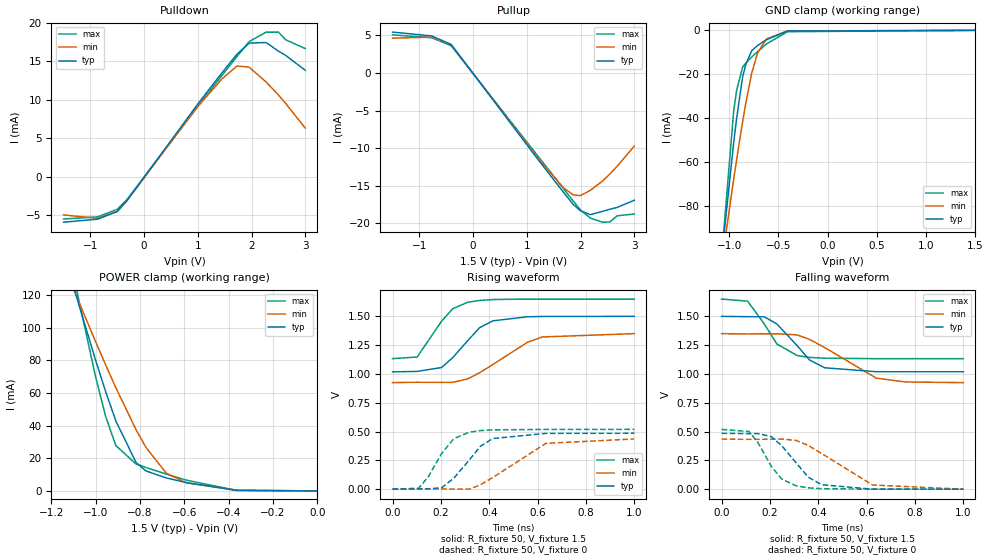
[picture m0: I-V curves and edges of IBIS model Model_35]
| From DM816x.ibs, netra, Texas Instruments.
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| Model based on original model for BSHTLTCSCDVGPBFZ
|   Sub model FAST_4MA_10PER_1P5
[model]   Model_35
|[Description]  1.5V-3-STATE-X-FAST, 4MA, +-10%
|[Input Load]
|[Output Drive] FAST, 4MA
|Voltage   1.5V
|Mode   3-STATE
Model_type   3-state
Polarity   Non-Inverting
Enable   Active-Low
Cref =  15.0000pF
Rref =  100.0000M
Vref =  0V
Vmeas =  0.75
C_comp   1.5249p   1.4275p   1.6205p
[Model Spec]
[Temperature Range]   25   125   -40
[Voltage Range]   1.5   1.35   1.65
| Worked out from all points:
|   slope of the pulldown table from 0 to 0.225 V, typ, clamps not added: 103 ohm
|   slope of the pullup table from 0 to 0.225 V, typ, clamps not added: 103 ohm
|   GND clamp passes 1 mA (typ) near -0.47 V on its own axis
|   POWER clamp passes 1 mA (typ) near -0.42 V on its own axis
|   rising waveform, R_fixture 50, V_fixture 1.5: 20-80 % time 125ps typ, 190ps min, 98.5ps max; typ from 1.02 V to 1.5 V
|   rising waveform, R_fixture 50, V_fixture 0: 20-80 % time 118ps typ, 179ps min, 93.9ps max; typ from 0 V to 0.485 V
|   falling waveform, R_fixture 50, V_fixture 1.5: 20-80 % time 123ps typ, 193ps min, 96.8ps max; typ from 1.5 V to 1.02 V
|   falling waveform, R_fixture 50, V_fixture 0: 20-80 % time 118ps typ, 186ps min, 92.7ps max; typ from 0.485 V to 0 V
[POWER_clamp]
-1.5V     321.6mA    260.6mA    415.8mA
-1.091V   121.1mA    120.8mA    126.6mA
-1.076V   114.1mA    115.8mA    116.8mA
-1V       79.88mA    91.3mA     69.56mA
-954.5mV  60.58mA    77.05mA    45.34mA
-909.1mV  42.84mA    63.2mA     27.8mA
-818.2mV  17.47mA    37.6mA     16.51mA
-772.7mV  12.19mA    26.53mA    14.33mA
-681.8mV  7.985mA    10.89mA    10.33mA
-590.9mV  5.092mA    4.952mA    6.596mA
-363.6mV  298.9uA    465.6uA    298.1uA
0V        1.518nA    23.05nA    396.5pA
[Pulldown]
-1.5V     -5.88mA    -4.94mA    -5.47mA
-863.6mV  -5.487mA   -5.379mA   -5.186mA
-500mV    -4.486mA   -4.503mA   -4.211mA
-318.2mV  -3.077mA   -3.07mA    -2.94mA
1V        9.473mA    9.16mA     9.156mA
1.455V    13.57mA    12.77mA    13.23mA
1.727V    15.92mA    14.4mA     15.62mA
1.955V    17.38mA    14.26mA    17.57mA
2.273V    17.45mA    12.32mA    18.81mA
2.5V      16.34mA    10.65mA    18.81mA
2.636V    15.78mA    9.54mA     17.81mA
3V        13.85mA    6.33mA     16.67mA
[Pullup]
-1.5V     5.43mA     4.62mA     5.06mA
-772.7mV  4.923mA    4.757mA    4.681mA
-409.1mV  3.79mA     3.753mA    3.62mA
1.227V    -11.69mA   -11.51mA   -11.25mA
1.682V    -15.87mA   -15.27mA   -15.39mA
1.864V    -17.48mA   -16.22mA   -17.03mA
2V        -18.33mA   -16.3mA    -18.23mA
2.182V    -18.84mA   -15.6mA    -19.29mA
2.409V    -18.4mA    -14.37mA   -19.84mA
2.545V    -18.12mA   -13.43mA   -19.81mA
2.682V    -17.87mA   -12.4mA    -18.99mA
3V        -16.92mA   -9.72mA    -18.75mA
[GND_clamp]
-1.5V     -310mA     -250.5mA   -402.4mA
-1.076V   -103.5mA   -106.1mA   -105.2mA
-1.045V   -89.74mA   -96.32mA   -85.93mA
-954.5mV  -51.19mA   -67.85mA   -36.85mA
-924.2mV  -40.06mA   -58.84mA   -27.27mA
-863.6mV  -21.23mA   -41.55mA   -16.73mA
-833.3mV  -15.79mA   -33.74mA   -15.03mA
-772.7mV  -9.342mA   -19.74mA   -12.19mA
-712.1mV  -6.927mA   -10.35mA   -9.702mA
-621.2mV  -4.26mA    -3.894mA   -6.224mA
-409.1mV  -336.9uA   -288.9uA   -618.6uA
1.5V      1.518nA    2.298uA    269.6pA
[Ramp]
dV/dt_f   0.38584/0.19087369n   0.340824/0.2796553n   0.41424/0.15390254n
dV/dt_r 0.38881204/0.18228362n 0.35035216/0.25786987n 0.41518698/0.14899493n
R_load = 50
[Rising Waveform]
R_fixture = 50
V_fixture = 1.5
V_fixture_min = 1.35
V_fixture_max = 1.65
0s        1.018V     925mV      1.133V
101.8ps   1.022V     927.9mV    1.147V
202.9ps   1.056V     926.8mV    1.458V
249.3ps   1.142V     927.2mV    1.567V
310.6ps   1.288V     956.7mV    1.622V
359.9ps   1.401V     1.01V      1.638V
415ps     1.461V     1.082V     1.646V
557.2ps   1.496V     1.274V     1.65V
619.4ps   1.499V     1.321V     1.65V
1ns       1.5V       1.35V      1.65V
[Rising Waveform]
R_fixture = 50
V_fixture = 0
V_fixture_min = 0
V_fixture_max = 0
0s        0V         0V         0V
108ps     3.692mV    3.336mV    8.042mV
148.5ps   2.516mV    2.612mV    109.7mV
203.4ps   12.94mV    2.18mV     310.8mV
253.5ps   95.47mV    0V         438.2mV
316.7ps   250.8mV    0V         494.3mV
362.5ps   370.4mV    36.85mV    508.2mV
414.5ps   439.3mV    100.9mV    514.7mV
634.5ps   484.3mV    397.9mV    518.8mV
1ns       485.4mV    435.6mV    518.9mV
[Falling Waveform]
R_fixture = 50
V_fixture = 1.5
V_fixture_min = 1.35
V_fixture_max = 1.65
0s        1.499V     1.349V     1.649V
107.7ps   1.496V     1.346V     1.631V
176.4ps   1.495V     1.348V     1.434V
228.8ps   1.433V     1.348V     1.259V
313ps     1.244V     1.338V     1.159V
363.6ps   1.121V     1.299V     1.143V
426.1ps   1.053V     1.229V     1.136V
640ps     1.019V     963mV      1.132V
760ps     1.018V     930mV      1.132V
1ns       1.018V     924.1mV    1.132V
[Falling Waveform]
R_fixture = 50
V_fixture = 0
V_fixture_min = 0
V_fixture_max = 0
0s        484.8mV    434.7mV    518.3mV
113.3ps   481.3mV    431.8mV    499.8mV
149.7ps   482.8mV    432.5mV    407.2mV
206ps     455.5mV    433.3mV    196.6mV
248.9ps   377.1mV    434.7mV    87.42mV
309.3ps   226.3mV    422.6mV    28.14mV
358.4ps   103.8mV    379.1mV    11.33mV
414ps     38.69mV    309.4mV    4.192mV
624.1ps   0V         36.17mV    0V
1ns       0V         0V         0V
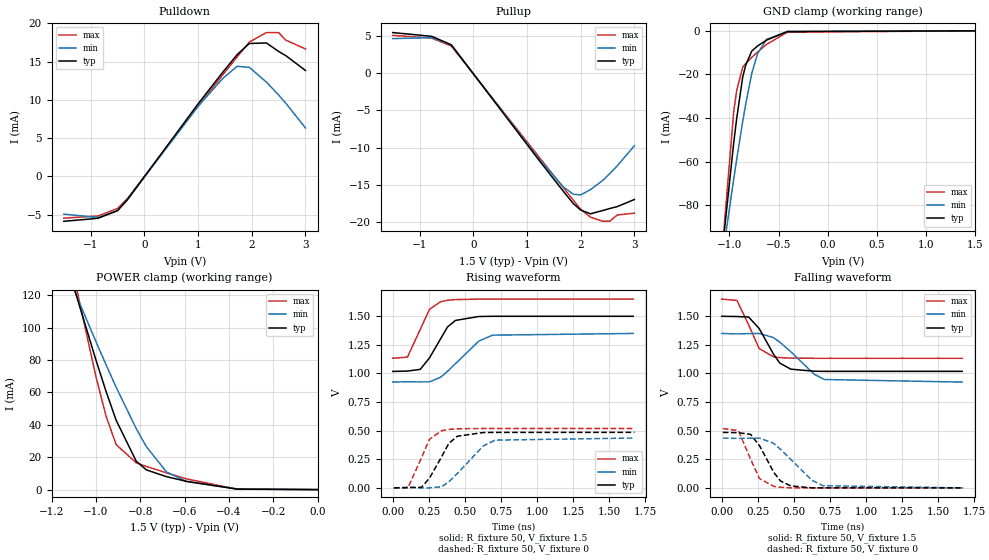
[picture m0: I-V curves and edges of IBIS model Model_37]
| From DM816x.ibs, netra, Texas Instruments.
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| Model based on original model for BSHTLTCSCDVGPBFZ
|   Sub model SLOW_4MA_10PER_1P5
[model]   Model_37
|[Description]  1.5V-3-STATE-X-SLOW, 4MA, +-10%
|[Input Load]
|[Output Drive] SLOW, 4MA
|Voltage   1.5V
|Mode   3-STATE
Model_type   3-state
Polarity   Non-Inverting
Enable   Active-Low
Cref =  15.0000pF
Rref =  100.0000M
Vref =  0V
Vmeas =  0.75
C_comp   1.5249p   1.4275p   1.6205p
[Model Spec]
[Temperature Range]   25   125   -40
[Voltage Range]   1.5   1.35   1.65
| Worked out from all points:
|   slope of the pulldown table from 0 to 0.225 V, typ, clamps not added: 103 ohm
|   slope of the pullup table from 0 to 0.225 V, typ, clamps not added: 103 ohm
|   GND clamp passes 1 mA (typ) near -0.47 V on its own axis
|   POWER clamp passes 1 mA (typ) near -0.42 V on its own axis
|   rising waveform, R_fixture 50, V_fixture 1.5: 20-80 % time 134ps typ, 210ps min, 103ps max; typ from 1.02 V to 1.5 V
|   rising waveform, R_fixture 50, V_fixture 0: 20-80 % time 127ps typ, 197ps min, 98.6ps max; typ from 0 V to 0.485 V
|   falling waveform, R_fixture 50, V_fixture 1.5: 20-80 % time 132ps typ, 216ps min, 101ps max; typ from 1.5 V to 1.02 V
|   falling waveform, R_fixture 50, V_fixture 0: 20-80 % time 128ps typ, 208ps min, 97.5ps max; typ from 0.485 V to 0 V
[POWER_clamp]
-1.5V     321.6mA    260.6mA    415.8mA
-1.091V   121.1mA    120.8mA    126.6mA
-1.076V   114.1mA    115.8mA    116.8mA
-1V       79.88mA    91.3mA     69.56mA
-954.5mV  60.58mA    77.05mA    45.34mA
-909.1mV  42.84mA    63.2mA     27.8mA
-818.2mV  17.47mA    37.6mA     16.51mA
-772.7mV  12.19mA    26.53mA    14.33mA
-681.8mV  7.985mA    10.89mA    10.33mA
-590.9mV  5.092mA    4.952mA    6.596mA
-363.6mV  298.9uA    465.6uA    298.1uA
0V        1.518nA    23.05nA    396.5pA
[Pulldown]
-1.5V     -5.88mA    -4.94mA    -5.47mA
-863.6mV  -5.487mA   -5.379mA   -5.186mA
-500mV    -4.486mA   -4.503mA   -4.211mA
-318.2mV  -3.077mA   -3.07mA    -2.94mA
1V        9.473mA    9.16mA     9.156mA
1.455V    13.57mA    12.77mA    13.23mA
1.727V    15.92mA    14.4mA     15.62mA
1.955V    17.38mA    14.26mA    17.57mA
2.273V    17.45mA    12.32mA    18.81mA
2.5V      16.34mA    10.65mA    18.81mA
2.636V    15.78mA    9.54mA     17.81mA
3V        13.85mA    6.33mA     16.67mA
[Pullup]
-1.5V     5.43mA     4.62mA     5.06mA
-772.7mV  4.923mA    4.757mA    4.681mA
-409.1mV  3.79mA     3.753mA    3.62mA
1.227V    -11.69mA   -11.51mA   -11.25mA
1.682V    -15.87mA   -15.27mA   -15.39mA
1.864V    -17.48mA   -16.22mA   -17.03mA
2V        -18.33mA   -16.3mA    -18.23mA
2.182V    -18.84mA   -15.6mA    -19.29mA
2.409V    -18.4mA    -14.37mA   -19.84mA
2.545V    -18.12mA   -13.43mA   -19.81mA
2.682V    -17.87mA   -12.4mA    -18.99mA
3V        -16.92mA   -9.72mA    -18.75mA
[GND_clamp]
-1.5V     -310mA     -250.5mA   -402.4mA
-1.076V   -103.5mA   -106.1mA   -105.2mA
-1.045V   -89.74mA   -96.32mA   -85.93mA
-954.5mV  -51.19mA   -67.85mA   -36.85mA
-924.2mV  -40.06mA   -58.84mA   -27.27mA
-863.6mV  -21.23mA   -41.55mA   -16.73mA
-833.3mV  -15.79mA   -33.74mA   -15.03mA
-772.7mV  -9.342mA   -19.74mA   -12.19mA
-712.1mV  -6.927mA   -10.35mA   -9.702mA
-621.2mV  -4.26mA    -3.894mA   -6.224mA
-409.1mV  -336.9uA   -288.9uA   -618.6uA
1.5V      1.518nA    2.298uA    269.6pA
[Ramp]
dV/dt_f   0.38584/0.20238725n   0.340824/0.3070203n   0.41424/0.15926272n
dV/dt_r 0.38895657/0.19261991n 0.35034264/0.28080709n 0.41518864/0.15432644n
R_load = 50
[Rising Waveform]
R_fixture = 50
V_fixture = 1.5
V_fixture_min = 1.35
V_fixture_max = 1.65
0s        1.018V     925mV      1.133V
102ps     1.021V     927.9mV    1.143V
190.6ps   1.036V     926.2mV    1.385V
254.8ps   1.136V     926.6mV    1.561V
331.2ps   1.302V     966.7mV    1.627V
379.2ps   1.406V     1.018V     1.64V
435ps     1.464V     1.086V     1.646V
596.8ps   1.498V     1.283V     1.65V
691.9ps   1.5V       1.335V     1.65V
1.667ns   1.5V       1.35V      1.65V
[Rising Waveform]
R_fixture = 50
V_fixture = 0
V_fixture_min = 0
V_fixture_max = 0
8.2ps     0V         0V         0V
105ps     3.063mV    3.518mV    0V
199.6ps   4.844mV    0V         263.3mV
254.7ps   85.08mV    0V         425.3mV
338.8ps   271.6mV    9.629mV    499.5mV
388.8ps   389.1mV    53.05mV    511mV
447.5ps   451.1mV    124.8mV    516.2mV
626.6ps   483.7mV    365.5mV    518.8mV
709.4ps   484.9mV    417.3mV    518.9mV
1.675ns   485.4mV    435.6mV    518.9mV
[Falling Waveform]
R_fixture = 50
V_fixture = 1.5
V_fixture_min = 1.35
V_fixture_max = 1.65
0s        1.499V     1.349V     1.649V
105.8ps   1.497V     1.345V     1.638V
187.3ps   1.492V     1.348V     1.423V
260.1ps   1.392V     1.349V     1.217V
359.2ps   1.168V     1.313V     1.145V
402.9ps   1.09V      1.273V     1.138V
479.5ps   1.037V     1.189V     1.134V
642.1ps   1.019V     992.1mV    1.132V
713.4ps   1.018V     946.8mV    1.132V
1.667ns   1.018V     924.1mV    1.132V
[Falling Waveform]
R_fixture = 50
V_fixture = 0
V_fixture_min = 0
V_fixture_max = 0
8.2ps     484.8mV    434.8mV    518.3mV
116ps     481.8mV    432mV      500.1mV
200.7ps   467.2mV    434mV      250.1mV
262.4ps   368.3mV    435mV      80.84mV
361.1ps   135.7mV    388.3mV    13.03mV
408ps     59.33mV    336.4mV    5.377mV
479.3ps   16.81mV    248.3mV    0V
625.2ps   0V         66.12mV    0V
702.9ps   0V         18.62mV    0V
1.675ns   0V         0V         0V
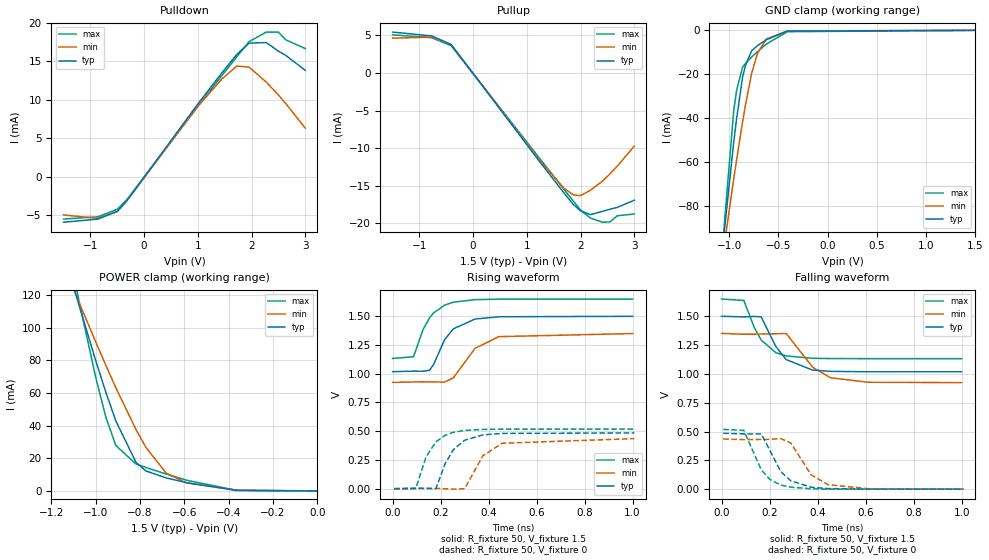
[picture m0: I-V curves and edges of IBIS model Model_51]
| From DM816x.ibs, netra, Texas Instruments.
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| Model based on original model for BSHTLTCSCDVGPBFZ
|   Sub model FASTEST_4MA_10PER_1P5
[model]   Model_51
|[Description]  1.5V-3-STATE-X-FASTEST, 4MA, +-10%
|[Input Load]
|[Output Drive] FASTEST, 4MA
|Voltage   1.5V
|Mode   3-STATE
Model_type   3-state
Polarity   Non-Inverting
Enable   Active-Low
Cref =  15.0000pF
Rref =  100.0000M
Vref =  0V
Vmeas =  0.75
C_comp   1.5249p   1.4275p   1.6205p
[Model Spec]
[Temperature Range]   25   125   -40
[Voltage Range]   1.5   1.35   1.65
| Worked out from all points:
|   slope of the pulldown table from 0 to 0.225 V, typ, clamps not added: 103 ohm
|   slope of the pullup table from 0 to 0.225 V, typ, clamps not added: 103 ohm
|   GND clamp passes 1 mA (typ) near -0.47 V on its own axis
|   POWER clamp passes 1 mA (typ) near -0.42 V on its own axis
|   rising waveform, R_fixture 50, V_fixture 1.5: 20-80 % time 82.5ps typ, 101ps min, 76.6ps max; typ from 1.02 V to 1.5 V
|   rising waveform, R_fixture 50, V_fixture 0: 20-80 % time 78.1ps typ, 85.8ps min, 73.3ps max; typ from 0 V to 0.485 V
|   falling waveform, R_fixture 50, V_fixture 1.5: 20-80 % time 86.7ps typ, 100ps min, 79.9ps max; typ from 1.5 V to 1.02 V
|   falling waveform, R_fixture 50, V_fixture 0: 20-80 % time 80.9ps typ, 90.6ps min, 74.7ps max; typ from 0.485 V to 0 V
[POWER_clamp]
-1.5V     321.6mA    260.6mA    415.8mA
-1.091V   121.1mA    120.8mA    126.6mA
-1.076V   114.1mA    115.8mA    116.8mA
-1V       79.88mA    91.3mA     69.56mA
-954.5mV  60.58mA    77.05mA    45.34mA
-909.1mV  42.84mA    63.2mA     27.8mA
-818.2mV  17.47mA    37.6mA     16.51mA
-772.7mV  12.19mA    26.53mA    14.33mA
-681.8mV  7.985mA    10.89mA    10.33mA
-590.9mV  5.092mA    4.952mA    6.596mA
-363.6mV  298.9uA    465.6uA    298.1uA
0V        1.518nA    23.05nA    396.5pA
[Pulldown]
-1.5V     -5.88mA    -4.94mA    -5.47mA
-863.6mV  -5.487mA   -5.379mA   -5.186mA
-500mV    -4.486mA   -4.503mA   -4.211mA
-318.2mV  -3.077mA   -3.07mA    -2.94mA
1V        9.473mA    9.16mA     9.156mA
1.455V    13.57mA    12.77mA    13.23mA
1.727V    15.92mA    14.4mA     15.62mA
1.955V    17.38mA    14.26mA    17.57mA
2.273V    17.45mA    12.32mA    18.81mA
2.5V      16.34mA    10.65mA    18.81mA
2.636V    15.78mA    9.54mA     17.81mA
3V        13.85mA    6.33mA     16.67mA
[Pullup]
-1.5V     5.43mA     4.62mA     5.06mA
-772.7mV  4.923mA    4.757mA    4.681mA
-409.1mV  3.79mA     3.753mA    3.62mA
1.227V    -11.69mA   -11.51mA   -11.25mA
1.682V    -15.87mA   -15.27mA   -15.39mA
1.864V    -17.48mA   -16.22mA   -17.03mA
2V        -18.33mA   -16.3mA    -18.23mA
2.182V    -18.84mA   -15.6mA    -19.29mA
2.409V    -18.4mA    -14.37mA   -19.84mA
2.545V    -18.12mA   -13.43mA   -19.81mA
2.682V    -17.87mA   -12.4mA    -18.99mA
3V        -16.92mA   -9.72mA    -18.75mA
[GND_clamp]
-1.5V     -310mA     -250.5mA   -402.4mA
-1.076V   -103.5mA   -106.1mA   -105.2mA
-1.045V   -89.74mA   -96.32mA   -85.93mA
-954.5mV  -51.19mA   -67.85mA   -36.85mA
-924.2mV  -40.06mA   -58.84mA   -27.27mA
-863.6mV  -21.23mA   -41.55mA   -16.73mA
-833.3mV  -15.79mA   -33.74mA   -15.03mA
-772.7mV  -9.342mA   -19.74mA   -12.19mA
-712.1mV  -6.927mA   -10.35mA   -9.702mA
-621.2mV  -4.26mA    -3.894mA   -6.224mA
-409.1mV  -336.9uA   -288.9uA   -618.6uA
1.5V      1.518nA    2.298uA    269.6pA
[Ramp]
dV/dt_f   0.38672/0.13661906n   0.342904/0.15870225n   0.41424/0.12503733n
dV/dt_r  0.3974704/0.12516981n   0.360196/0.13960142n 0.41930096/0.11673466n
R_load = 50
[Rising Waveform]
R_fixture = 50
V_fixture = 1.5
V_fixture_min = 1.35
V_fixture_max = 1.65
0s        1.018V     925mV      1.133V
87.39ps   1.023V     928.5mV    1.148V
127.1ps   1.022V     930.3mV    1.384V
153.7ps   1.03V      929mV      1.485V
170.6ps   1.079V     929mV      1.529V
216.7ps   1.296V     927.6mV    1.597V
253.3ps   1.391V     964.6mV    1.623V
343.5ps   1.476V     1.221V     1.645V
442.6ps   1.496V     1.323V     1.649V
1ns       1.5V       1.35V      1.65V
[Rising Waveform]
R_fixture = 50
V_fixture = 0
V_fixture_min = 0
V_fixture_max = 0
6.86ps    0V         0V         0V
96.36ps   4.181mV    3.088mV    0V
140.3ps   0V         4.674mV    279.9mV
180.5ps   0V         2.367mV    407.1mV
219.2ps   219mV      0V         464.7mV
253.5ps   340.2mV    -4.126mV   490.7mV
300.6ps   421.6mV    0V         507mV
375.9ps   468.2mV    285.7mV    515.8mV
456.6ps   481.1mV    395.6mV    518.1mV
1.007ns   485.4mV    435.6mV    518.9mV
[Falling Waveform]
R_fixture = 50
V_fixture = 1.5
V_fixture_min = 1.35
V_fixture_max = 1.65
0s        1.5V       1.351V     1.649V
92.66ps   1.494V     1.344V     1.637V
136.1ps   1.498V     1.344V     1.403V
164.8ps   1.495V     1.346V     1.294V
226ps     1.237V     1.348V     1.184V
269.3ps   1.124V     1.35V      1.156V
379.1ps   1.033V     1.058V     1.135V
454ps     1.022V     966.2mV    1.133V
609.6ps   1.018V     927.4mV    1.132V
1ns       1.018V     924.1mV    1.132V
[Falling Waveform]
R_fixture = 50
V_fixture = 0
V_fixture_min = 0
V_fixture_max = 0
6.86ps    485mV      435.3mV    518.3mV
92.21ps   479.3mV    429.6mV    510.1mV
165.6ps   478.8mV    431.5mV    167mV
201.7ps   333.4mV    432.9mV    83.94mV
246.5ps   153.3mV    438.4mV    35.66mV
288.5ps   72.6mV     400.4mV    16.78mV
372.9ps   16.68mV    125mV      3.546mV
443.6ps   4.714mV    38.52mV    0V
631.3ps   0V         0V         0V
1.007ns   0V         0V         0V
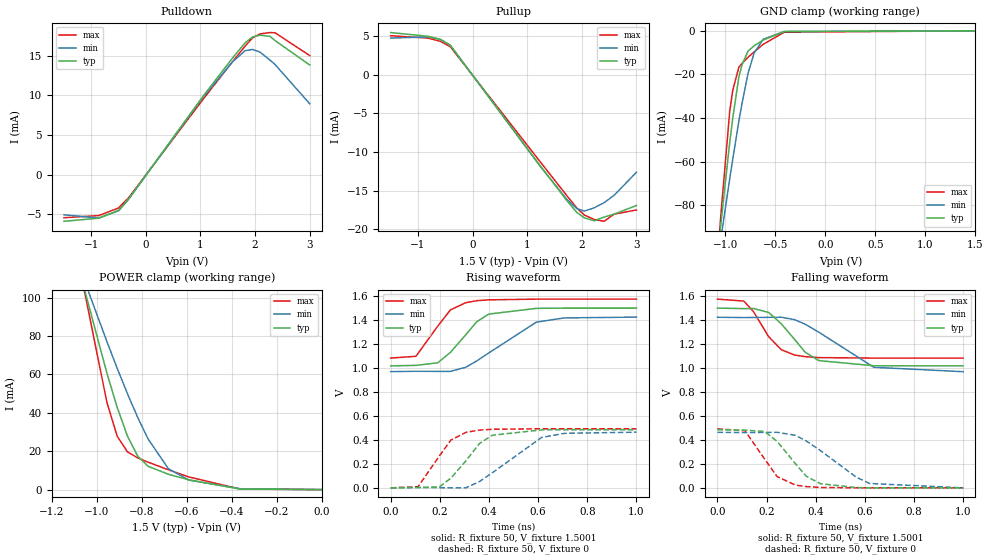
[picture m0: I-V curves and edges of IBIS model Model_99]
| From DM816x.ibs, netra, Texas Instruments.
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| Model based on original model for BSHTLTCSCDVGPBFZ
|   Sub model FAST_4MA_5PER_1P5
[model]   Model_99
|[Description]  1.5V-3-STATE-X-FAST, 4MA, +-5%
|[Input Load]
|[Output Drive] FAST, 4MA
|Voltage   1.5V
|Mode   3-STATE
Model_type   3-state
Polarity   Non-Inverting
Enable   Active-Low
Cref =  15.0000pF
Rref =  100.0000M
Vref =  0V
Vmeas =  0.75005
C_comp   1.5249p   1.4275p   1.6205p
[Model Spec]
[Temperature Range]   25   125   -40
[Voltage Range]   1.5   1.425   1.575
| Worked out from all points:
|   slope of the pulldown table from 0 to 0.225 V, typ, clamps not added: 103 ohm
|   slope of the pullup table from 0 to 0.225 V, typ, clamps not added: 103 ohm
|   GND clamp passes 1 mA (typ) near -0.47 V on its own axis
|   POWER clamp passes 1 mA (typ) near -0.42 V on its own axis
|   rising waveform, R_fixture 50, V_fixture 1.5001: 20-80 % time 125ps typ, 191ps min, 98.7ps max; typ from 1.02 V to 1.5 V
|   rising waveform, R_fixture 50, V_fixture 0: 20-80 % time 118ps typ, 179ps min, 94ps max; typ from 0 V to 0.485 V
|   falling waveform, R_fixture 50, V_fixture 1.5001: 20-80 % time 123ps typ, 193ps min, 96.8ps max; typ from 1.5 V to 1.02 V
|   falling waveform, R_fixture 50, V_fixture 0: 20-80 % time 118ps typ, 186ps min, 92.9ps max; typ from 0.485 V to 0 V
[POWER_clamp]
-1.5V     321.7mA    260.6mA    415.9mA
-1.076V   114.2mA    115.8mA    116.9mA
-1.061V   107.2mA    110.9mA    107.1mA
-954.6mV  60.59mA    77.06mA    45.35mA
-909.2mV  42.85mA    63.21mA    27.81mA
-863.7mV  27.9mA     49.99mA    19.69mA
-818.2mV  17.49mA    37.63mA    16.52mA
-772.8mV  12.19mA    26.53mA    14.33mA
-681.9mV  7.985mA    10.89mA    10.33mA
-590.9mV  5.094mA    4.955mA    6.6mA
-363.7mV  298.5uA    465.2uA    297.6uA
0V        1.518nA    24.08nA    367.8pA
[Pulldown]
-1.5V     -5.88mA    -5.06mA    -5.43mA
-863.7mV  -5.487mA   -5.465mA   -5.158mA
-500mV    -4.487mA   -4.559mA   -4.195mA
-318.2mV  -3.078mA   -3.107mA   -2.93mA
1.046V    9.891mA    9.776mA    9.509mA
1.591V    14.76mA    14.27mA    14.3mA
1.818V    16.65mA    15.66mA    16.24mA
1.955V    17.39mA    15.81mA    17.28mA
2.091V    17.61mA    15.47mA    17.77mA
2.273V    17.46mA    14.46mA    17.94mA
2.364V    16.94mA    13.92mA    17.92mA
3V        13.85mA    8.96mA     15.04mA
[Pullup]
-1.5V     5.43mA     4.72mA     5.02mA
-818.2mV  4.951mA    4.862mA    4.719mA
-590.9mV  4.551mA    4.546mA    4.297mA
-409.1mV  3.79mA     3.793mA    3.605mA
1.227V    -11.69mA   -11.75mA   -11.17mA
1.727V    -16.29mA   -16.13mA   -15.66mA
1.909V    -17.82mA   -17.32mA   -17.25mA
2.046V    -18.51mA   -17.64mA   -18.15mA
2.227V    -18.89mA   -17.22mA   -18.72mA
2.409V    -18.41mA   -16.55mA   -18.96mA
2.591V    -18.04mA   -15.6mA    -18.04mA
3V        -16.92mA   -12.63mA   -17.5mA
[GND_clamp]
-1.5V     -310.1mA   -250.5mA   -402.5mA
-1.076V   -103.6mA   -106.2mA   -105.2mA
-1.046V   -89.81mA   -96.36mA   -86.02mA
-954.6mV  -51.22mA   -67.87mA   -36.88mA
-924.3mV  -40.08mA   -58.86mA   -27.29mA
-863.7mV  -21.24mA   -41.56mA   -16.73mA
-833.4mV  -15.8mA    -33.75mA   -15.03mA
-772.8mV  -9.345mA   -19.75mA   -12.19mA
-712.2mV  -6.928mA   -10.35mA   -9.704mA
-621.3mV  -4.261mA   -3.896mA   -6.225mA
-409.1mV  -337.1uA   -289.1uA   -618.9uA
1.5V      1.518nA    257.2nA    299pA
[Ramp]
dV/dt_f   0.38592/0.19102821n   0.364576/0.27842816n   0.39392/0.15463627n
dV/dt_r 0.38883599/0.18228677n 0.37365912/0.25774358n 0.39461704/0.14969139n
R_load = 50
[Rising Waveform]
R_fixture = 50
V_fixture = 1.5001
V_fixture_min = 1.425
V_fixture_max = 1.575
0s        1.018V     969.9mV    1.083V
102.6ps   1.022V     973mV      1.098V
191.9ps   1.044V     972mV      1.351V
243ps     1.131V     972.2mV    1.485V
304.9ps   1.276V     1.006V     1.545V
350ps     1.386V     1.059V     1.562V
399ps     1.45V      1.126V     1.569V
592.8ps   1.498V     1.383V     1.575V
705.1ps   1.5V       1.418V     1.575V
1ns       1.5V       1.425V     1.575V
[Rising Waveform]
R_fixture = 50
V_fixture = 0
V_fixture_min = 0
V_fixture_max = 0
0s        0V         0V         0V
111.4ps   3.567mV    3.153mV    9.879mV
197.7ps   7.603mV    2.207mV    265.2mV
245ps     81.01mV    0V         399.1mV
305.8ps   225.1mV    0V         463mV
361.5ps   370.4mV    52.94mV    482.3mV
413.5ps   439.3mV    125.7mV    488.9mV
614.1ps   483.8mV    420.7mV    493.1mV
709.2ps   485.1mV    455.3mV    493.2mV
1ns       485.4mV    464.7mV    493.2mV
[Falling Waveform]
R_fixture = 50
V_fixture = 1.5001
V_fixture_min = 1.425
V_fixture_max = 1.575
0s        1.5V       1.424V     1.575V
107.1ps   1.496V     1.421V     1.559V
146.1ps   1.497V     1.422V     1.472V
208.2ps   1.464V     1.423V     1.262V
259.9ps   1.369V     1.424V     1.153V
313.2ps   1.241V     1.404V     1.109V
356.8ps   1.132V     1.366V     1.095V
412.7ps   1.062V     1.299V     1.087V
636.6ps   1.019V     1.006V     1.083V
1ns       1.018V     969.4mV    1.083V
[Falling Waveform]
R_fixture = 50
V_fixture = 0
V_fixture_min = 0
V_fixture_max = 0
0s        484.8mV    463.8mV    492.4mV
112.1ps   481.3mV    460.9mV    476.9mV
191.5ps   470.5mV    462.7mV    241.8mV
242.9ps   388mV      463.7mV    93.96mV
317ps     202.3mV    438.6mV    23.27mV
361.2ps   97.02mV    391.4mV    10.58mV
419.9ps   34.18mV    310.3mV    3.527mV
564.7ps   2.879mV    89.15mV    0V
619.7ps   0V         36.39mV    0V
1ns       0V         0V         0V
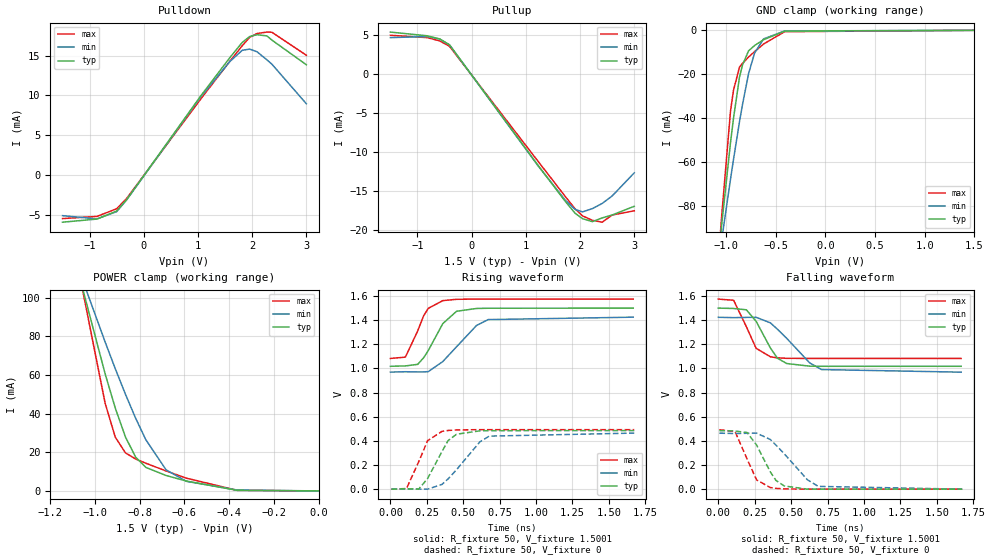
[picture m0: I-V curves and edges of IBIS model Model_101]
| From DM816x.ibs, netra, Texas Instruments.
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| Model based on original model for BSHTLTCSCDVGPBFZ
|   Sub model SLOW_4MA_5PER_1P5
[model]   Model_101
|[Description]  1.5V-3-STATE-X-SLOW, 4MA, +-5%
|[Input Load]
|[Output Drive] SLOW, 4MA
|Voltage   1.5V
|Mode   3-STATE
Model_type   3-state
Polarity   Non-Inverting
Enable   Active-Low
Cref =  15.0000pF
Rref =  100.0000M
Vref =  0V
Vmeas =  0.75005
C_comp   1.5249p   1.4275p   1.6205p
[Model Spec]
[Temperature Range]   25   125   -40
[Voltage Range]   1.5   1.425   1.575
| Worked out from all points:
|   slope of the pulldown table from 0 to 0.225 V, typ, clamps not added: 103 ohm
|   slope of the pullup table from 0 to 0.225 V, typ, clamps not added: 103 ohm
|   GND clamp passes 1 mA (typ) near -0.47 V on its own axis
|   POWER clamp passes 1 mA (typ) near -0.42 V on its own axis
|   rising waveform, R_fixture 50, V_fixture 1.5001: 20-80 % time 134ps typ, 209ps min, 104ps max; typ from 1.02 V to 1.5 V
|   rising waveform, R_fixture 50, V_fixture 0: 20-80 % time 127ps typ, 198ps min, 98.9ps max; typ from 0 V to 0.485 V
|   falling waveform, R_fixture 50, V_fixture 1.5001: 20-80 % time 132ps typ, 216ps min, 101ps max; typ from 1.5 V to 1.02 V
|   falling waveform, R_fixture 50, V_fixture 0: 20-80 % time 128ps typ, 209ps min, 97.5ps max; typ from 0.485 V to 0 V
[POWER_clamp]
-1.5V     321.7mA    260.6mA    415.9mA
-1.076V   114.2mA    115.8mA    116.9mA
-1.061V   107.2mA    110.9mA    107.1mA
-954.6mV  60.59mA    77.06mA    45.35mA
-909.2mV  42.85mA    63.21mA    27.81mA
-863.7mV  27.9mA     49.99mA    19.69mA
-818.2mV  17.49mA    37.63mA    16.52mA
-772.8mV  12.19mA    26.53mA    14.33mA
-681.9mV  7.985mA    10.89mA    10.33mA
-590.9mV  5.094mA    4.955mA    6.6mA
-363.7mV  298.5uA    465.2uA    297.6uA
0V        1.518nA    24.08nA    367.8pA
[Pulldown]
-1.5V     -5.88mA    -5.06mA    -5.43mA
-863.7mV  -5.487mA   -5.465mA   -5.158mA
-500mV    -4.487mA   -4.559mA   -4.195mA
-318.2mV  -3.078mA   -3.107mA   -2.93mA
1.046V    9.891mA    9.776mA    9.509mA
1.591V    14.76mA    14.27mA    14.3mA
1.818V    16.65mA    15.66mA    16.24mA
1.955V    17.39mA    15.81mA    17.28mA
2.091V    17.61mA    15.47mA    17.77mA
2.273V    17.46mA    14.46mA    17.94mA
2.364V    16.94mA    13.92mA    17.92mA
3V        13.85mA    8.96mA     15.04mA
[Pullup]
-1.5V     5.43mA     4.72mA     5.02mA
-818.2mV  4.951mA    4.862mA    4.719mA
-590.9mV  4.551mA    4.546mA    4.297mA
-409.1mV  3.79mA     3.793mA    3.605mA
1.227V    -11.69mA   -11.75mA   -11.17mA
1.727V    -16.29mA   -16.13mA   -15.66mA
1.909V    -17.82mA   -17.32mA   -17.25mA
2.046V    -18.51mA   -17.64mA   -18.15mA
2.227V    -18.89mA   -17.22mA   -18.72mA
2.409V    -18.41mA   -16.55mA   -18.96mA
2.591V    -18.04mA   -15.6mA    -18.04mA
3V        -16.92mA   -12.63mA   -17.5mA
[GND_clamp]
-1.5V     -310.1mA   -250.5mA   -402.5mA
-1.076V   -103.6mA   -106.2mA   -105.2mA
-1.046V   -89.81mA   -96.36mA   -86.02mA
-954.6mV  -51.22mA   -67.87mA   -36.88mA
-924.3mV  -40.08mA   -58.86mA   -27.29mA
-863.7mV  -21.24mA   -41.56mA   -16.73mA
-833.4mV  -15.8mA    -33.75mA   -15.03mA
-772.8mV  -9.345mA   -19.75mA   -12.19mA
-712.2mV  -6.928mA   -10.35mA   -9.704mA
-621.3mV  -4.261mA   -3.896mA   -6.225mA
-409.1mV  -337.1uA   -289.1uA   -618.9uA
1.5V      1.518nA    257.2nA    299pA
[Ramp]
dV/dt_f   0.38592/0.20232841n   0.364576/0.3061353n   0.39392/0.16026431n
dV/dt_r 0.38898084/0.19262657n 0.37343304/0.28112391n 0.39461866/0.15520228n
R_load = 50
[Rising Waveform]
R_fixture = 50
V_fixture = 1.5001
V_fixture_min = 1.425
V_fixture_max = 1.575
0s        1.018V     969.9mV    1.083V
103ps     1.021V     973mV      1.094V
187.5ps   1.034V     971.3mV    1.311V
228.2ps   1.089V     971.4mV    1.437V
260.3ps   1.149V     974.1mV    1.498V
359.5ps   1.371V     1.057V     1.562V
454.3ps   1.474V     1.18V      1.573V
591.1ps   1.497V     1.356V     1.575V
671ps     1.499V     1.405V     1.575V
1.667ns   1.5V       1.425V     1.575V
[Rising Waveform]
R_fixture = 50
V_fixture = 0
V_fixture_min = 0
V_fixture_max = 0
7.64ps    0V         0V         0V
110.6ps   3.296mV    3.086mV    5.159mV
194.2ps   0V         0V         226.8mV
255.3ps   88mV       0V         401.5mV
353.4ps   310mV      38.85mV    478.4mV
395.7ps   401.7mV    84.49mV    486.4mV
453.8ps   455mV      161mV      490.7mV
614.8ps   483.4mV    392.6mV    493.1mV
678.7ps   484.7mV    439.5mV    493.2mV
1.674ns   485.4mV    464.7mV    493.2mV
[Falling Waveform]
R_fixture = 50
V_fixture = 1.5001
V_fixture_min = 1.425
V_fixture_max = 1.575
0s        1.5V       1.424V     1.575V
105.2ps   1.497V     1.421V     1.565V
192.6ps   1.486V     1.423V     1.346V
259.5ps   1.391V     1.424V     1.167V
357.4ps   1.17V      1.378V     1.097V
406.1ps   1.085V     1.325V     1.088V
469.3ps   1.041V     1.25V      1.084V
627.4ps   1.019V     1.046V     1.083V
708.6ps   1.018V     990.9mV    1.083V
1.667ns   1.018V     969.4mV    1.083V
[Falling Waveform]
R_fixture = 50
V_fixture = 0
V_fixture_min = 0
V_fixture_max = 0
7.64ps    484.8mV    463.9mV    492.3mV
114.7ps   481.9mV    461.1mV    477.3mV
197.7ps   469.1mV    463.1mV    249.6mV
262.8ps   365.3mV    464.3mV    76.96mV
356.8ps   143.5mV    411.6mV    13.13mV
395.5ps   72.87mV    365.4mV    6.589mV
452.3ps   26.59mV    293.5mV    2.444mV
611.7ps   0V         77.89mV    0V
685.9ps   0V         23.07mV    0V
1.674ns   0V         0V         0V
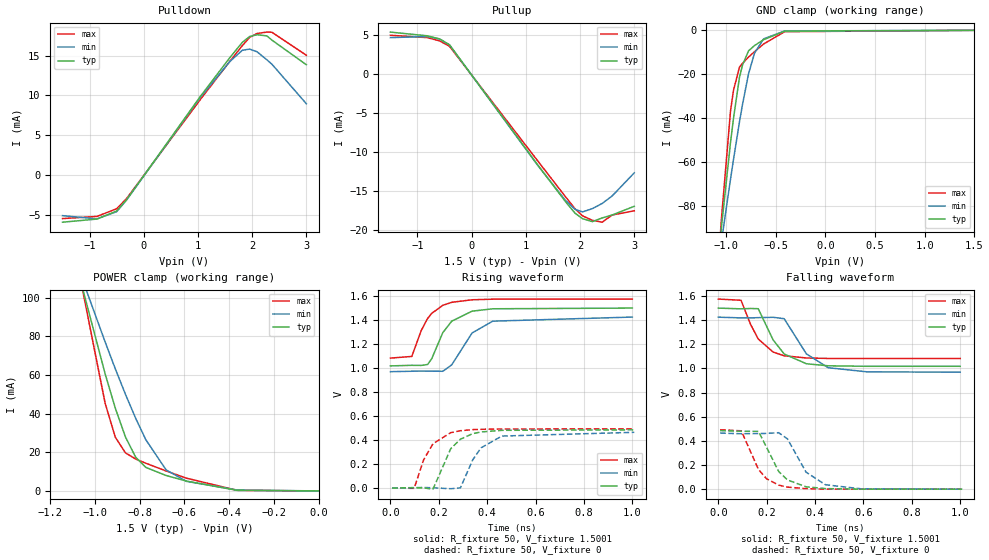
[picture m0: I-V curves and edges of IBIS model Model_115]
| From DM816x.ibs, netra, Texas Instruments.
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| Model based on original model for BSHTLTCSCDVGPBFZ
|   Sub model FASTEST_4MA_5PER_1P5
[model]   Model_115
|[Description]  1.5V-3-STATE-X-FASTEST, 4MA, +-5%
|[Input Load]
|[Output Drive] FASTEST, 4MA
|Voltage   1.5V
|Mode   3-STATE
Model_type   3-state
Polarity   Non-Inverting
Enable   Active-Low
Cref =  15.0000pF
Rref =  100.0000M
Vref =  0V
Vmeas =  0.75005
C_comp   1.5249p   1.4275p   1.6205p
[Model Spec]
[Temperature Range]   25   125   -40
[Voltage Range]   1.5   1.425   1.575
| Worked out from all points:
|   slope of the pulldown table from 0 to 0.225 V, typ, clamps not added: 103 ohm
|   slope of the pullup table from 0 to 0.225 V, typ, clamps not added: 103 ohm
|   GND clamp passes 1 mA (typ) near -0.47 V on its own axis
|   POWER clamp passes 1 mA (typ) near -0.42 V on its own axis
|   rising waveform, R_fixture 50, V_fixture 1.5001: 20-80 % time 82.5ps typ, 96.6ps min, 76.4ps max; typ from 1.02 V to 1.5 V
|   rising waveform, R_fixture 50, V_fixture 0: 20-80 % time 78.1ps typ, 84.6ps min, 73.8ps max; typ from 0 V to 0.485 V
|   falling waveform, R_fixture 50, V_fixture 1.5001: 20-80 % time 86.8ps typ, 98ps min, 80.2ps max; typ from 1.5 V to 1.02 V
|   falling waveform, R_fixture 50, V_fixture 0: 20-80 % time 80.9ps typ, 89.2ps min, 75.3ps max; typ from 0.485 V to 0 V
[POWER_clamp]
-1.5V     321.7mA    260.6mA    415.9mA
-1.076V   114.2mA    115.8mA    116.9mA
-1.061V   107.2mA    110.9mA    107.1mA
-954.6mV  60.59mA    77.06mA    45.35mA
-909.2mV  42.85mA    63.21mA    27.81mA
-863.7mV  27.9mA     49.99mA    19.69mA
-818.2mV  17.49mA    37.63mA    16.52mA
-772.8mV  12.19mA    26.53mA    14.33mA
-681.9mV  7.985mA    10.89mA    10.33mA
-590.9mV  5.094mA    4.955mA    6.6mA
-363.7mV  298.5uA    465.2uA    297.6uA
0V        1.518nA    24.08nA    367.8pA
[Pulldown]
-1.5V     -5.88mA    -5.06mA    -5.43mA
-863.7mV  -5.487mA   -5.465mA   -5.158mA
-500mV    -4.487mA   -4.559mA   -4.195mA
-318.2mV  -3.078mA   -3.107mA   -2.93mA
1.046V    9.891mA    9.776mA    9.509mA
1.591V    14.76mA    14.27mA    14.3mA
1.818V    16.65mA    15.66mA    16.24mA
1.955V    17.39mA    15.81mA    17.28mA
2.091V    17.61mA    15.47mA    17.77mA
2.273V    17.46mA    14.46mA    17.94mA
2.364V    16.94mA    13.92mA    17.92mA
3V        13.85mA    8.96mA     15.04mA
[Pullup]
-1.5V     5.43mA     4.72mA     5.02mA
-818.2mV  4.951mA    4.862mA    4.719mA
-590.9mV  4.551mA    4.546mA    4.297mA
-409.1mV  3.79mA     3.793mA    3.605mA
1.227V    -11.69mA   -11.75mA   -11.17mA
1.727V    -16.29mA   -16.13mA   -15.66mA
1.909V    -17.82mA   -17.32mA   -17.25mA
2.046V    -18.51mA   -17.64mA   -18.15mA
2.227V    -18.89mA   -17.22mA   -18.72mA
2.409V    -18.41mA   -16.55mA   -18.96mA
2.591V    -18.04mA   -15.6mA    -18.04mA
3V        -16.92mA   -12.63mA   -17.5mA
[GND_clamp]
-1.5V     -310.1mA   -250.5mA   -402.5mA
-1.076V   -103.6mA   -106.2mA   -105.2mA
-1.046V   -89.81mA   -96.36mA   -86.02mA
-954.6mV  -51.22mA   -67.87mA   -36.88mA
-924.3mV  -40.08mA   -58.86mA   -27.29mA
-863.7mV  -21.24mA   -41.56mA   -16.73mA
-833.4mV  -15.8mA    -33.75mA   -15.03mA
-772.8mV  -9.345mA   -19.75mA   -12.19mA
-712.2mV  -6.928mA   -10.35mA   -9.704mA
-621.3mV  -4.261mA   -3.896mA   -6.225mA
-409.1mV  -337.1uA   -289.1uA   -618.9uA
1.5V      1.518nA    257.2nA    299pA
[Ramp]
dV/dt_f   0.3868/0.13666195n   0.366416/0.1559588n   0.39392/0.12712193n
dV/dt_r  0.3974944/0.12516544n  0.3836488/0.13631969n 0.39905696/0.11746637n
R_load = 50
[Rising Waveform]
R_fixture = 50
V_fixture = 1.5001
V_fixture_min = 1.425
V_fixture_max = 1.575
0s        1.018V     969.9mV    1.083V
88.39ps   1.023V     973.6mV    1.097V
127.5ps   1.022V     975.6mV    1.313V
154ps     1.03V      974.1mV    1.414V
171ps     1.079V     974.1mV    1.456V
216.6ps   1.295V     973.3mV    1.523V
253.6ps   1.391V     1.027V     1.548V
337.5ps   1.474V     1.292V     1.569V
423.2ps   1.494V     1.391V     1.574V
1ns       1.5V       1.425V     1.575V
[Rising Waveform]
R_fixture = 50
V_fixture = 0
V_fixture_min = 0
V_fixture_max = 0
7.68ps    0V         0V         0V
98.28ps   4.09mV     3.071mV    -2.032mV
136.8ps   2.005mV    5.152mV    233.5mV
176.1ps   -8.917mV   2.456mV    369.7mV
249.4ps   328.3mV    -5.292mV   461.9mV
289.4ps   407.4mV    2.035mV    478.1mV
340.1ps   453.5mV    234.6mV    487.2mV
374.8ps   467.8mV    335.5mV    490mV
460.4ps   481.3mV    433.5mV    492.5mV
1.008ns   485.4mV    464.7mV    493.2mV
[Falling Waveform]
R_fixture = 50
V_fixture = 1.5001
V_fixture_min = 1.425
V_fixture_max = 1.575
0s        1.5V       1.425V     1.575V
93.86ps   1.494V     1.419V     1.565V
133.5ps   1.497V     1.419V     1.365V
165.1ps   1.495V     1.421V     1.244V
226.4ps   1.237V     1.424V     1.136V
272.3ps   1.12V      1.412V     1.105V
364.1ps   1.039V     1.121V     1.087V
454.5ps   1.022V     1.006V     1.083V
615.5ps   1.018V     971.9mV    1.083V
1ns       1.018V     969.4mV    1.083V
[Falling Waveform]
R_fixture = 50
V_fixture = 0
V_fixture_min = 0
V_fixture_max = 0
7.68ps    485mV      464.7mV    492.4mV
95ps      479.6mV    459mV      483.5mV
166ps     478.9mV    460.6mV    163.2mV
199.3ps   347.9mV    461.8mV    86.62mV
249.5ps   146.7mV    468mV      33.32mV
286.2ps   76.11mV    415.7mV    17.06mV
362.8ps   19.47mV    140.6mV    4.301mV
442.9ps   4.776mV    36.55mV    0V
588.8ps   0V         3.215mV    0V
1.008ns   0V         0V         0V
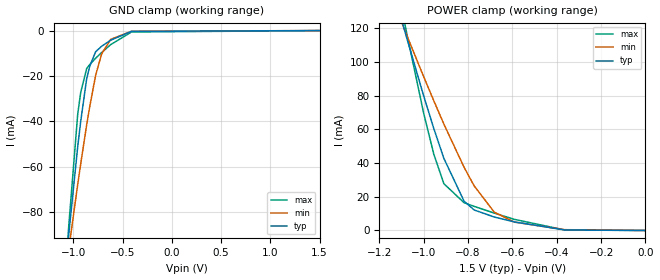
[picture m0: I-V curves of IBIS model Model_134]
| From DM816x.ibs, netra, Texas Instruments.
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| Model based on original model for BSHTLTCSCDVGPBFZ
|   Sub model REC_NOTERM_10PER_1P5
[model]   Model_134
|[Description]  1.5V-INPUT-NOTERM-X, +-10%
|[Input Load]   NOTERM
|[Output Drive]
|Voltage   1.5V
|Mode   INPUT
Model_type   Input
Polarity   Non-Inverting
Vinl =  0.65
Vinh =  1
C_comp   1.5249p   1.4275p   1.6205p
[Model Spec]
Vinl   0.65   0.65   0.65
Vinh   1   1   1
[Temperature Range]   25   125   -40
[Voltage Range]   1.5   1.35   1.65
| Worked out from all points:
|   GND clamp passes 1 mA (typ) near -0.47 V on its own axis
|   POWER clamp passes 1 mA (typ) near -0.42 V on its own axis
[POWER_clamp]
-1.5V     321.6mA    260.6mA    415.8mA
-1.091V   121.1mA    120.8mA    126.6mA
-1.076V   114.1mA    115.8mA    116.8mA
-1V       79.88mA    91.3mA     69.56mA
-954.5mV  60.58mA    77.05mA    45.34mA
-909.1mV  42.84mA    63.2mA     27.8mA
-818.2mV  17.47mA    37.6mA     16.51mA
-772.7mV  12.19mA    26.53mA    14.33mA
-681.8mV  7.985mA    10.89mA    10.33mA
-590.9mV  5.092mA    4.952mA    6.596mA
-363.6mV  298.9uA    465.6uA    298.1uA
0V        1.518nA    23.05nA    396.5pA
[GND_clamp]
-1.5V     -310mA     -250.5mA   -402.4mA
-1.076V   -103.5mA   -106.1mA   -105.2mA
-1.045V   -89.74mA   -96.32mA   -85.93mA
-954.5mV  -51.19mA   -67.85mA   -36.85mA
-924.2mV  -40.06mA   -58.84mA   -27.27mA
-863.6mV  -21.23mA   -41.55mA   -16.73mA
-833.3mV  -15.79mA   -33.74mA   -15.03mA
-772.7mV  -9.342mA   -19.74mA   -12.19mA
-712.1mV  -6.927mA   -10.35mA   -9.702mA
-621.2mV  -4.26mA    -3.894mA   -6.224mA
-409.1mV  -336.9uA   -288.9uA   -618.6uA
1.5V      1.518nA    2.298uA    269.6pA
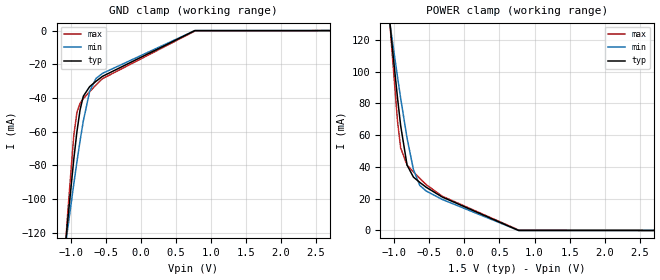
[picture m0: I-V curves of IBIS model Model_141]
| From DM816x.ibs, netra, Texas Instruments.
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| Model based on original model for BSHTLTCSCDVGPBFZ
|   Sub model REC_FULLTERM_5PER_1P5
[model]   Model_141
|[Description]  1.5V-INPUT-FULLTERM-X, +-5%
|[Input Load]   FULLTERM
|[Output Drive]
|Voltage   1.5V
|Mode   INPUT
Model_type   Input
Polarity   Non-Inverting
Vinl =  0.6125
Vinh =  0.9625
C_comp   1.5249p   1.4275p   1.6205p
[Model Spec]
Vinl   0.6125   0.6125   0.6125
Vinh   0.9625   0.9625   0.9625
[Temperature Range]   25   125   -40
[Voltage Range]   1.5   1.425   1.575
[POWER_clamp]
-1.5V     342.3mA    275.7mA    437.3mA
-1.091V   143.7mA    139.6mA    149.7mA
-1.046V   122.9mA    125.1mA    120.4mA
-954.6mV  83.55mA    96.8mA     69mA
-909.2mV  65.98mA    83.23mA    51.97mA
-818.2mV  41.15mA    58.15mA    41.18mA
-727.3mV  33.6mA     38.36mA    36.86mA
-636.4mV  30.26mA    28.37mA    32.77mA
-545.5mV  27.22mA    24.85mA    28.87mA
-318.2mV  21.1mA     19.57mA    21.61mA
772.8mV   0A         0A         294.7uA
3V        0A         0A         0A
[GND_clamp]
-1.5V     -334.4mA   -269.8mA   -427.4mA
-1.091V   -135.7mA   -133.7mA   -140mA
-1.046V   -115.1mA   -119.3mA   -111.2mA
-954.6mV  -76.62mA   -91.21mA   -62.46mA
-909.2mV  -60.01mA   -77.87mA   -48.55mA
-863.7mV  -46.93mA   -65.23mA   -43.02mA
-818.2mV  -38.98mA   -53.64mA   -40.41mA
-727.3mV  -33.23mA   -36mA      -36.22mA
-636.4mV  -30.06mA   -28.37mA   -32.26mA
-545.5mV  -27.17mA   -25.39mA   -28.56mA
772.8mV   0A         0A         -285.7uA
3V        0A         0A         0A
